VERSION 5.7 ;
  NOWIREEXTENSIONATPIN ON ;
  DIVIDERCHAR "/" ;
  BUSBITCHARS "[]" ;
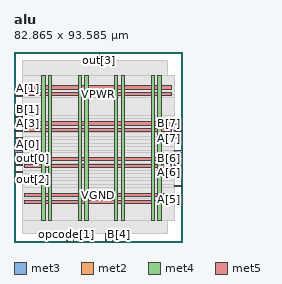
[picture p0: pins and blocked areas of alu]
MACRO alu
  CLASS BLOCK ;
  FOREIGN alu ;
  ORIGIN 0.000 0.000 ;
  SIZE 82.865 BY 93.585 ;
  PIN A[0]
    DIRECTION INPUT ;
    USE SIGNAL ;
    ANTENNAGATEAREA 0.196500 ;
    PORT
      LAYER met3 ;
        RECT 0.000 44.240 4.000 44.840 ;
    END
  END A[0]
  PIN A[1]
    DIRECTION INPUT ;
    USE SIGNAL ;
    ANTENNAGATEAREA 0.159000 ;
    PORT
      LAYER met3 ;
        RECT 0.000 71.440 4.000 72.040 ;
    END
  END A[1]
  PIN A[2]
    DIRECTION INPUT ;
    USE SIGNAL ;
    ANTENNAGATEAREA 0.196500 ;
    PORT
      LAYER met3 ;
        RECT 0.000 54.440 4.000 55.040 ;
    END
  END A[2]
  PIN A[3]
    DIRECTION INPUT ;
    USE SIGNAL ;
    ANTENNAGATEAREA 0.196500 ;
    PORT
      LAYER met3 ;
        RECT 0.000 57.840 4.000 58.440 ;
    END
  END A[3]
  PIN A[4]
    DIRECTION INPUT ;
    USE SIGNAL ;
    ANTENNAGATEAREA 0.126000 ;
    PORT
      LAYER met2 ;
        RECT 45.170 0.000 45.450 4.000 ;
    END
  END A[4]
  PIN A[5]
    DIRECTION INPUT ;
    USE SIGNAL ;
    ANTENNAGATEAREA 0.126000 ;
    PORT
      LAYER met3 ;
        RECT 78.865 20.440 82.865 21.040 ;
    END
  END A[5]
  PIN A[6]
    DIRECTION INPUT ;
    USE SIGNAL ;
    ANTENNAGATEAREA 0.213000 ;
    PORT
      LAYER met3 ;
        RECT 78.865 37.440 82.865 38.040 ;
    END
  END A[6]
  PIN A[7]
    DIRECTION INPUT ;
    USE SIGNAL ;
    ANTENNAGATEAREA 0.196500 ;
    PORT
      LAYER met3 ;
        RECT 78.865 54.440 82.865 55.040 ;
    END
  END A[7]
  PIN B[0]
    DIRECTION INPUT ;
    USE SIGNAL ;
    ANTENNAGATEAREA 0.213000 ;
    PORT
      LAYER met3 ;
        RECT 0.000 34.040 4.000 34.640 ;
    END
  END B[0]
  PIN B[1]
    DIRECTION INPUT ;
    USE SIGNAL ;
    ANTENNAGATEAREA 0.196500 ;
    PORT
      LAYER met3 ;
        RECT 0.000 61.240 4.000 61.840 ;
    END
  END B[1]
  PIN B[2]
    DIRECTION INPUT ;
    USE SIGNAL ;
    ANTENNAGATEAREA 0.196500 ;
    PORT
      LAYER met3 ;
        RECT 0.000 47.640 4.000 48.240 ;
    END
  END B[2]
  PIN B[3]
    DIRECTION INPUT ;
    USE SIGNAL ;
    ANTENNAGATEAREA 0.196500 ;
    PORT
      LAYER met3 ;
        RECT 0.000 37.440 4.000 38.040 ;
    END
  END B[3]
  PIN B[4]
    DIRECTION INPUT ;
    USE SIGNAL ;
    ANTENNAGATEAREA 0.213000 ;
    PORT
      LAYER met2 ;
        RECT 51.610 0.000 51.890 4.000 ;
    END
  END B[4]
  PIN B[5]
    DIRECTION INPUT ;
    USE SIGNAL ;
    ANTENNAGATEAREA 0.126000 ;
    PORT
      LAYER met2 ;
        RECT 54.830 0.000 55.110 4.000 ;
    END
  END B[5]
  PIN B[6]
    DIRECTION INPUT ;
    USE SIGNAL ;
    ANTENNAGATEAREA 0.126000 ;
    ANTENNADIFFAREA 0.434700 ;
    PORT
      LAYER met3 ;
        RECT 78.865 40.840 82.865 41.440 ;
    END
  END B[6]
  PIN B[7]
    DIRECTION INPUT ;
    USE SIGNAL ;
    ANTENNAGATEAREA 0.196500 ;
    PORT
      LAYER met3 ;
        RECT 78.865 57.840 82.865 58.440 ;
    END
  END B[7]
  PIN VGND
    DIRECTION INOUT ;
    USE GROUND ;
    PORT
      LAYER met4 ;
        RECT 16.990 10.640 18.590 81.840 ;
    END
    PORT
      LAYER met4 ;
        RECT 34.930 10.640 36.530 81.840 ;
    END
    PORT
      LAYER met4 ;
        RECT 52.870 10.640 54.470 81.840 ;
    END
    PORT
      LAYER met4 ;
        RECT 70.810 10.640 72.410 81.840 ;
    END
    PORT
      LAYER met5 ;
        RECT 5.280 22.220 77.520 23.820 ;
    END
    PORT
      LAYER met5 ;
        RECT 5.280 39.900 77.520 41.500 ;
    END
    PORT
      LAYER met5 ;
        RECT 5.280 57.580 77.520 59.180 ;
    END
    PORT
      LAYER met5 ;
        RECT 5.280 75.260 77.520 76.860 ;
    END
  END VGND
  PIN VPWR
    DIRECTION INOUT ;
    USE POWER ;
    PORT
      LAYER met4 ;
        RECT 13.690 10.640 15.290 81.840 ;
    END
    PORT
      LAYER met4 ;
        RECT 31.630 10.640 33.230 81.840 ;
    END
    PORT
      LAYER met4 ;
        RECT 49.570 10.640 51.170 81.840 ;
    END
    PORT
      LAYER met4 ;
        RECT 67.510 10.640 69.110 81.840 ;
    END
    PORT
      LAYER met5 ;
        RECT 5.280 18.920 77.520 20.520 ;
    END
    PORT
      LAYER met5 ;
        RECT 5.280 36.600 77.520 38.200 ;
    END
    PORT
      LAYER met5 ;
        RECT 5.280 54.280 77.520 55.880 ;
    END
    PORT
      LAYER met5 ;
        RECT 5.280 71.960 77.520 73.560 ;
    END
  END VPWR
  PIN opcode[0]
    DIRECTION INPUT ;
    USE SIGNAL ;
    ANTENNAGATEAREA 0.196500 ;
    PORT
      LAYER met2 ;
        RECT 29.070 0.000 29.350 4.000 ;
    END
  END opcode[0]
  PIN opcode[1]
    DIRECTION INPUT ;
    USE SIGNAL ;
    ANTENNAGATEAREA 0.126000 ;
    PORT
      LAYER met2 ;
        RECT 25.850 0.000 26.130 4.000 ;
    END
  END opcode[1]
  PIN opcode[2]
    DIRECTION INPUT ;
    USE SIGNAL ;
    ANTENNAGATEAREA 0.159000 ;
    PORT
      LAYER met2 ;
        RECT 32.290 0.000 32.570 4.000 ;
    END
  END opcode[2]
  PIN out[0]
    DIRECTION OUTPUT ;
    USE SIGNAL ;
    ANTENNADIFFAREA 0.445500 ;
    PORT
      LAYER met3 ;
        RECT 0.000 40.840 4.000 41.440 ;
    END
  END out[0]
  PIN out[1]
    DIRECTION OUTPUT ;
    USE SIGNAL ;
    ANTENNADIFFAREA 0.445500 ;
    PORT
      LAYER met3 ;
        RECT 0.000 51.040 4.000 51.640 ;
    END
  END out[1]
  PIN out[2]
    DIRECTION OUTPUT ;
    USE SIGNAL ;
    ANTENNADIFFAREA 0.445500 ;
    PORT
      LAYER met3 ;
        RECT 0.000 30.640 4.000 31.240 ;
    END
  END out[2]
  PIN out[3]
    DIRECTION OUTPUT ;
    USE SIGNAL ;
    ANTENNADIFFAREA 0.795200 ;
    PORT
      LAYER met2 ;
        RECT 41.950 89.585 42.230 93.585 ;
    END
  END out[3]
  PIN out[4]
    DIRECTION OUTPUT ;
    USE SIGNAL ;
    ANTENNADIFFAREA 0.445500 ;
    PORT
      LAYER met2 ;
        RECT 48.390 0.000 48.670 4.000 ;
    END
  END out[4]
  PIN out[5]
    DIRECTION OUTPUT ;
    USE SIGNAL ;
    ANTENNADIFFAREA 0.445500 ;
    PORT
      LAYER met3 ;
        RECT 78.865 27.240 82.865 27.840 ;
    END
  END out[5]
  PIN out[6]
    DIRECTION OUTPUT ;
    USE SIGNAL ;
    ANTENNADIFFAREA 0.445500 ;
    PORT
      LAYER met3 ;
        RECT 78.865 44.240 82.865 44.840 ;
    END
  END out[6]
  PIN out[7]
    DIRECTION OUTPUT ;
    USE SIGNAL ;
    ANTENNADIFFAREA 0.445500 ;
    PORT
      LAYER met3 ;
        RECT 78.865 51.040 82.865 51.640 ;
    END
  END out[7]
  OBS
      LAYER nwell ;
        RECT 5.330 10.795 77.470 81.685 ;
      LAYER li1 ;
        RECT 5.520 10.795 77.280 81.685 ;
      LAYER met1 ;
        RECT 4.210 10.640 77.280 81.840 ;
      LAYER met2 ;
        RECT 4.230 89.305 41.670 89.585 ;
        RECT 42.510 89.305 75.810 89.585 ;
        RECT 4.230 4.280 75.810 89.305 ;
        RECT 4.230 4.000 25.570 4.280 ;
        RECT 26.410 4.000 28.790 4.280 ;
        RECT 29.630 4.000 32.010 4.280 ;
        RECT 32.850 4.000 44.890 4.280 ;
        RECT 45.730 4.000 48.110 4.280 ;
        RECT 48.950 4.000 51.330 4.280 ;
        RECT 52.170 4.000 54.550 4.280 ;
        RECT 55.390 4.000 75.810 4.280 ;
      LAYER met3 ;
        RECT 3.990 72.440 78.865 81.765 ;
        RECT 4.400 71.040 78.865 72.440 ;
        RECT 3.990 62.240 78.865 71.040 ;
        RECT 4.400 60.840 78.865 62.240 ;
        RECT 3.990 58.840 78.865 60.840 ;
        RECT 4.400 57.440 78.465 58.840 ;
        RECT 3.990 55.440 78.865 57.440 ;
        RECT 4.400 54.040 78.465 55.440 ;
        RECT 3.990 52.040 78.865 54.040 ;
        RECT 4.400 50.640 78.465 52.040 ;
        RECT 3.990 48.640 78.865 50.640 ;
        RECT 4.400 47.240 78.865 48.640 ;
        RECT 3.990 45.240 78.865 47.240 ;
        RECT 4.400 43.840 78.465 45.240 ;
        RECT 3.990 41.840 78.865 43.840 ;
        RECT 4.400 40.440 78.465 41.840 ;
        RECT 3.990 38.440 78.865 40.440 ;
        RECT 4.400 37.040 78.465 38.440 ;
        RECT 3.990 35.040 78.865 37.040 ;
        RECT 4.400 33.640 78.865 35.040 ;
        RECT 3.990 31.640 78.865 33.640 ;
        RECT 4.400 30.240 78.865 31.640 ;
        RECT 3.990 28.240 78.865 30.240 ;
        RECT 3.990 26.840 78.465 28.240 ;
        RECT 3.990 21.440 78.865 26.840 ;
        RECT 3.990 20.040 78.465 21.440 ;
        RECT 3.990 10.715 78.865 20.040 ;
  END
END alu
END LIBRARY

